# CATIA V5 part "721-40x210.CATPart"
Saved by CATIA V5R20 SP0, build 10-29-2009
Part number: 721-40x210
Definition: NONE
Nomenclature: 721-40x210
Source: Unknown
Description: 721-40x210
Bounding box of the stored display mesh (mm): x -90 to 120, y -35 to 35, z -35 to 35
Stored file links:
  C:\Users\Utente\Desktop\IO LAVORO\3D X SITO CF\X SITO\721\721-40x210.CATPart

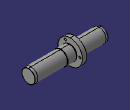
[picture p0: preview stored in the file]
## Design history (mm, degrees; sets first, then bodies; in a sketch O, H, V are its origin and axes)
Body1 "721-40x210" (main body)
  Solid1: solid without history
